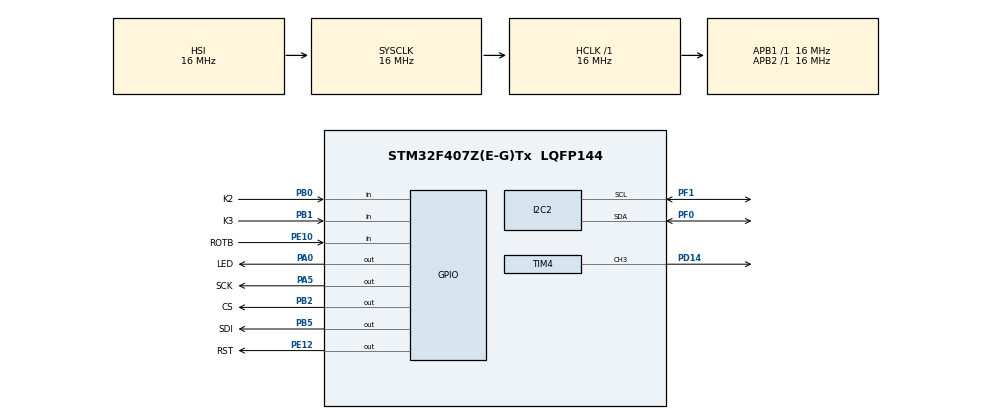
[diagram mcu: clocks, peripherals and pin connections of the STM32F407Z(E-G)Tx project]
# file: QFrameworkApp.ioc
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Mcu.Family=STM32F4
Mcu.Name=STM32F407Z(E-G)Tx
Mcu.Package=LQFP144
NVIC.PriorityGroup=NVIC_PRIORITYGROUP_4
PA0-WKUP.GPIO_Label=LED
PA0-WKUP.Signal=GPIO_Output
PA5.GPIO_Label=SCK
PA5.Signal=GPIO_Output
PB0.GPIO_Label=K2
PB0.Signal=GPIO_Input
PB1.GPIO_Label=K3
PB1.Signal=GPIO_Input
PB2.GPIO_Label=CS
PB2.Signal=GPIO_Output
PB5.GPIO_Label=SDI
PB5.PinState=GPIO_PIN_SET
PB5.Signal=GPIO_Output
PD14.Signal=S_TIM4_CH3
PE10.GPIO_Label=ROTB
PE10.GPIO_PuPd=GPIO_PULLDOWN
PE10.Signal=GPIO_Input
PE12.GPIO_Label=RST
PE12.PinState=GPIO_PIN_SET
PE12.Signal=GPIO_Output
PF0.Mode=I2C
PF0.Signal=I2C2_SDA
PF1.Mode=I2C
PF1.Signal=I2C2_SCL
ProjectManager.HeapSize=0x200
ProjectManager.StackSize=0x400
ProjectManager.TargetToolchain=STM32CubeIDE
RCC.AHBFreq_Value=16000000
RCC.APB1Freq_Value=16000000
RCC.APB2Freq_Value=16000000
RCC.CortexFreq_Value=16000000
RCC.HSE_VALUE=25000000
RCC.HSI_VALUE=16000000
RCC.LSE_VALUE=32768
RCC.SYSCLKFreq_VALUE=16000000
RCC.VCOOutputFreq_Value=192000000
SH.S_TIM4_CH3.0=TIM4_CH3,PWM Generation3 CH3
TIM4.Channel-PWM\ Generation3\ CH3=TIM_CHANNEL_3
TIM4.Period=4000
TIM4.Pulse-PWM\ Generation3\ CH3=2000
board=custom

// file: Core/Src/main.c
/* USER CODE BEGIN Header */
/**
  ******************************************************************************
  * @file           : main.c
  * @brief          : Main program body
  ******************************************************************************
  * @attention
  *
  * Copyright (c) 2022 STMicroelectronics.
  * All rights reserved.
  *
  * This software is licensed under terms that can be found in the LICENSE file
  * in the root directory of this software component.
  * If no LICENSE file comes with this software, it is provided AS-IS.
  *
  ******************************************************************************
  */
/* USER CODE END Header */
#include "main.h"

/* USER CODE BEGIN Includes */
#include "qpc.h"
#include "actorA.h"

// Q_DEFINE_THIS_MODULE("main")
Q_DEFINE_THIS_FILE

/* USER CODE END Includes */

I2C_HandleTypeDef hi2c2;

TIM_HandleTypeDef htim4;

void SystemClock_Config(void);
static void MX_GPIO_Init(void);
static void MX_TIM4_Init(void);
static void MX_I2C2_Init(void);

/* USER CODE BEGIN 0 */
QEvt const *l_blinkyQSto[10];
int _buff[1024];

/* USER CODE END 0 */

int main(void)
{

  /* MCU Configuration--------------------------------------------------------*/

  /* Reset of all peripherals, Initializes the Flash interface and the Systick. */
  HAL_Init();

  /* Configure the system clock */
  SystemClock_Config();

  /* Initialize all configured peripherals */
  MX_GPIO_Init();
  MX_TIM4_Init();
  MX_I2C2_Init();
  /* USER CODE BEGIN 2 */
  QF_init();
  QF_poolInit(_buff, 1024 * 4, 16);

  /* instantiate and start the active objects... */
  actorA_ctor();
  QACTIVE_START(AO_actorA,      /* AO pointer to start */
                1U,             /* unique QP priority of the AO */
                l_blinkyQSto,   /* storage for the AO's queue */
                Q_DIM(l_blinkyQSto), /* lenght of the queue [entries] */
                (void *)0,      /* stack storage (not used in QK) */
                0U,             /* stack size [bytes] (not used in QK) */
                (QEvt *)0);     /* initial event (or 0) */

  return QF_run(); /* run the QF application */

  /* USER CODE END 2 */

  /* Infinite loop */
  while (1)
  {

  }
}

void SystemClock_Config(void)
{
  RCC_OscInitTypeDef RCC_OscInitStruct = {0};
  RCC_ClkInitTypeDef RCC_ClkInitStruct = {0};

  /** Configure the main internal regulator output voltage
  */
  __HAL_RCC_PWR_CLK_ENABLE();
  __HAL_PWR_VOLTAGESCALING_CONFIG(PWR_REGULATOR_VOLTAGE_SCALE1);

  /** Initializes the RCC Oscillators according to the specified parameters
  * in the RCC_OscInitTypeDef structure.
  */
  RCC_OscInitStruct.OscillatorType = RCC_OSCILLATORTYPE_HSI;
  RCC_OscInitStruct.HSIState = RCC_HSI_ON;
  RCC_OscInitStruct.HSICalibrationValue = RCC_HSICALIBRATION_DEFAULT;
  RCC_OscInitStruct.PLL.PLLState = RCC_PLL_NONE;
  if (HAL_RCC_OscConfig(&RCC_OscInitStruct) != HAL_OK)
  {
    Error_Handler();
  }

  /** Initializes the CPU, AHB and APB buses clocks
  */
  RCC_ClkInitStruct.ClockType = RCC_CLOCKTYPE_HCLK|RCC_CLOCKTYPE_SYSCLK
                              |RCC_CLOCKTYPE_PCLK1|RCC_CLOCKTYPE_PCLK2;
  RCC_ClkInitStruct.SYSCLKSource = RCC_SYSCLKSOURCE_HSI;
  RCC_ClkInitStruct.AHBCLKDivider = RCC_SYSCLK_DIV1;
  RCC_ClkInitStruct.APB1CLKDivider = RCC_HCLK_DIV1;
  RCC_ClkInitStruct.APB2CLKDivider = RCC_HCLK_DIV1;

  if (HAL_RCC_ClockConfig(&RCC_ClkInitStruct, FLASH_LATENCY_0) != HAL_OK)
  {
    Error_Handler();
  }
}

static void MX_I2C2_Init(void)
{

  hi2c2.Instance = I2C2;
  hi2c2.Init.ClockSpeed = 100000;
  hi2c2.Init.DutyCycle = I2C_DUTYCYCLE_2;
  hi2c2.Init.OwnAddress1 = 0;
  hi2c2.Init.AddressingMode = I2C_ADDRESSINGMODE_7BIT;
  hi2c2.Init.DualAddressMode = I2C_DUALADDRESS_DISABLE;
  hi2c2.Init.OwnAddress2 = 0;
  hi2c2.Init.GeneralCallMode = I2C_GENERALCALL_DISABLE;
  hi2c2.Init.NoStretchMode = I2C_NOSTRETCH_DISABLE;
  if (HAL_I2C_Init(&hi2c2) != HAL_OK)
  {
    Error_Handler();
  }

}

static void MX_TIM4_Init(void)
{

  TIM_MasterConfigTypeDef sMasterConfig = {0};
  TIM_OC_InitTypeDef sConfigOC = {0};

  htim4.Instance = TIM4;
  htim4.Init.Prescaler = 0;
  htim4.Init.CounterMode = TIM_COUNTERMODE_UP;
  htim4.Init.Period = 4000;
  htim4.Init.ClockDivision = TIM_CLOCKDIVISION_DIV1;
  htim4.Init.AutoReloadPreload = TIM_AUTORELOAD_PRELOAD_DISABLE;
  if (HAL_TIM_PWM_Init(&htim4) != HAL_OK)
  {
    Error_Handler();
  }
  sMasterConfig.MasterOutputTrigger = TIM_TRGO_RESET;
  sMasterConfig.MasterSlaveMode = TIM_MASTERSLAVEMODE_DISABLE;
  if (HAL_TIMEx_MasterConfigSynchronization(&htim4, &sMasterConfig) != HAL_OK)
  {
    Error_Handler();
  }
  sConfigOC.OCMode = TIM_OCMODE_PWM1;
  sConfigOC.Pulse = 2000;
  sConfigOC.OCPolarity = TIM_OCPOLARITY_HIGH;
  sConfigOC.OCFastMode = TIM_OCFAST_DISABLE;
  if (HAL_TIM_PWM_ConfigChannel(&htim4, &sConfigOC, TIM_CHANNEL_3) != HAL_OK)
  {
    Error_Handler();
  }
  HAL_TIM_MspPostInit(&htim4);

}

static void MX_GPIO_Init(void)
{
  GPIO_InitTypeDef GPIO_InitStruct = {0};

  /* GPIO Ports Clock Enable */
  __HAL_RCC_GPIOF_CLK_ENABLE();
  __HAL_RCC_GPIOA_CLK_ENABLE();
  __HAL_RCC_GPIOB_CLK_ENABLE();
  __HAL_RCC_GPIOE_CLK_ENABLE();
  __HAL_RCC_GPIOD_CLK_ENABLE();

  /*Configure GPIO pin Output Level */
  HAL_GPIO_WritePin(GPIOA, LED_Pin|MTRX_CCLK_Pin|MTRX_CS_Pin|SCK_Pin, GPIO_PIN_RESET);

  /*Configure GPIO pin Output Level */
  HAL_GPIO_WritePin(CS_GPIO_Port, CS_Pin, GPIO_PIN_RESET);

  /*Configure GPIO pin Output Level */
  HAL_GPIO_WritePin(MTRX_LRST_GPIO_Port, MTRX_LRST_Pin, GPIO_PIN_RESET);

  /*Configure GPIO pin Output Level */
  HAL_GPIO_WritePin(RST_GPIO_Port, RST_Pin, GPIO_PIN_SET);

  /*Configure GPIO pin Output Level */
  HAL_GPIO_WritePin(MTRX_CRST_GPIO_Port, MTRX_CRST_Pin, GPIO_PIN_RESET);

  /*Configure GPIO pin Output Level */
  HAL_GPIO_WritePin(SDI_GPIO_Port, SDI_Pin, GPIO_PIN_SET);

  /*Configure GPIO pins : LED_Pin MTRX_CCLK_Pin MTRX_CS_Pin SCK_Pin */
  GPIO_InitStruct.Pin = LED_Pin|MTRX_CCLK_Pin|MTRX_CS_Pin|SCK_Pin;
  GPIO_InitStruct.Mode = GPIO_MODE_OUTPUT_PP;
  GPIO_InitStruct.Pull = GPIO_NOPULL;
  GPIO_InitStruct.Speed = GPIO_SPEED_FREQ_LOW;
  HAL_GPIO_Init(GPIOA, &GPIO_InitStruct);

  /*Configure GPIO pins : K2_Pin K3_Pin */
  GPIO_InitStruct.Pin = K2_Pin|K3_Pin;
  GPIO_InitStruct.Mode = GPIO_MODE_INPUT;
  GPIO_InitStruct.Pull = GPIO_NOPULL;
  HAL_GPIO_Init(GPIOB, &GPIO_InitStruct);

  /*Configure GPIO pins : CS_Pin SDI_Pin */
  GPIO_InitStruct.Pin = CS_Pin|SDI_Pin;
  GPIO_InitStruct.Mode = GPIO_MODE_OUTPUT_PP;
  GPIO_InitStruct.Pull = GPIO_NOPULL;
  GPIO_InitStruct.Speed = GPIO_SPEED_FREQ_LOW;
  HAL_GPIO_Init(GPIOB, &GPIO_InitStruct);

  /*Configure GPIO pin : ROTB_Pin */
  GPIO_InitStruct.Pin = ROTB_Pin;
  GPIO_InitStruct.Mode = GPIO_MODE_INPUT;
  GPIO_InitStruct.Pull = GPIO_PULLDOWN;
  HAL_GPIO_Init(ROTB_GPIO_Port, &GPIO_InitStruct);

  /*Configure GPIO pins : MTRX_LRST_Pin RST_Pin */
  GPIO_InitStruct.Pin = MTRX_LRST_Pin|RST_Pin;
  GPIO_InitStruct.Mode = GPIO_MODE_OUTPUT_PP;
  GPIO_InitStruct.Pull = GPIO_NOPULL;
  GPIO_InitStruct.Speed = GPIO_SPEED_FREQ_LOW;
  HAL_GPIO_Init(GPIOE, &GPIO_InitStruct);

  /*Configure GPIO pin : MTRX_CRST_Pin */
  GPIO_InitStruct.Pin = MTRX_CRST_Pin;
  GPIO_InitStruct.Mode = GPIO_MODE_OUTPUT_PP;
  GPIO_InitStruct.Pull = GPIO_NOPULL;
  GPIO_InitStruct.Speed = GPIO_SPEED_FREQ_LOW;
  HAL_GPIO_Init(MTRX_CRST_GPIO_Port, &GPIO_InitStruct);

}

void Error_Handler(void)
{
  __disable_irq();
  while (1)
  {
  }
}
